VERSION 5.7 ;
  NOWIREEXTENSIONATPIN ON ;
  DIVIDERCHAR "/" ;
  BUSBITCHARS "[]" ;
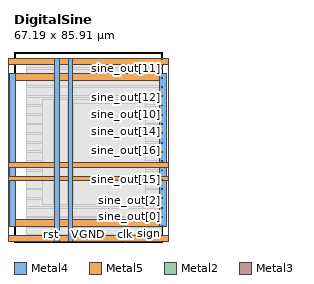
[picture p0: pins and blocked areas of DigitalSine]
MACRO DigitalSine
  CLASS BLOCK ;
  FOREIGN DigitalSine ;
  ORIGIN 0.000 0.000 ;
  SIZE 67.190 BY 85.910 ;
  PIN VGND
    DIRECTION INOUT ;
    USE GROUND ;
    PORT
      LAYER Metal4 ;
        RECT -9.240 0.120 -6.240 83.040 ;
    END
    PORT
      LAYER Metal4 ;
        RECT 72.960 0.120 75.960 83.040 ;
    END
    PORT
      LAYER Metal5 ;
        RECT -9.240 0.120 75.960 3.120 ;
    END
    PORT
      LAYER Metal5 ;
        RECT -9.240 80.040 75.960 83.040 ;
    END
    PORT
      LAYER Metal4 ;
        RECT 24.460 0.120 26.660 83.040 ;
    END
    PORT
      LAYER Metal5 ;
        RECT -9.240 33.820 75.960 36.020 ;
    END
  END VGND
  PIN VPWR
    DIRECTION INOUT ;
    USE POWER ;
    PORT
      LAYER Metal4 ;
        RECT -2.240 7.120 0.760 76.040 ;
    END
    PORT
      LAYER Metal4 ;
        RECT 65.960 7.120 68.960 76.040 ;
    END
    PORT
      LAYER Metal5 ;
        RECT -2.240 7.120 68.960 10.120 ;
    END
    PORT
      LAYER Metal5 ;
        RECT -2.240 73.040 68.960 76.040 ;
    END
    PORT
      LAYER Metal4 ;
        RECT 18.260 0.120 20.460 83.040 ;
    END
    PORT
      LAYER Metal5 ;
        RECT -9.240 27.620 75.960 29.820 ;
    END
  END VPWR
  PIN clk
    DIRECTION INPUT ;
    USE SIGNAL ;
    ANTENNAGATEAREA 1.450800 ;
    PORT
      LAYER Metal2 ;
        RECT 50.200 0.000 50.600 0.400 ;
    END
  END clk
  PIN rst
    DIRECTION INPUT ;
    USE SIGNAL ;
    ANTENNAGATEAREA 0.180700 ;
    PORT
      LAYER Metal2 ;
        RECT 16.600 0.000 17.000 0.400 ;
    END
  END rst
  PIN sign
    DIRECTION OUTPUT ;
    USE SIGNAL ;
    ANTENNADIFFAREA 0.708600 ;
    PORT
      LAYER Metal3 ;
        RECT 66.790 6.940 67.190 7.340 ;
    END
  END sign
  PIN signB
    DIRECTION OUTPUT ;
    USE SIGNAL ;
    ANTENNADIFFAREA 0.708600 ;
    PORT
      LAYER Metal3 ;
        RECT 66.790 2.740 67.190 3.140 ;
    END
  END signB
  PIN sine_out[0]
    DIRECTION OUTPUT ;
    USE SIGNAL ;
    ANTENNADIFFAREA 0.708600 ;
    PORT
      LAYER Metal3 ;
        RECT 66.790 11.140 67.190 11.540 ;
    END
  END sine_out[0]
  PIN sine_out[10]
    DIRECTION OUTPUT ;
    USE SIGNAL ;
    ANTENNADIFFAREA 0.708600 ;
    PORT
      LAYER Metal3 ;
        RECT 66.790 57.340 67.190 57.740 ;
    END
  END sine_out[10]
  PIN sine_out[11]
    DIRECTION OUTPUT ;
    USE SIGNAL ;
    ANTENNADIFFAREA 0.708600 ;
    PORT
      LAYER Metal3 ;
        RECT 66.790 78.340 67.190 78.740 ;
    END
  END sine_out[11]
  PIN sine_out[12]
    DIRECTION OUTPUT ;
    USE SIGNAL ;
    ANTENNADIFFAREA 0.708600 ;
    PORT
      LAYER Metal3 ;
        RECT 66.790 61.540 67.190 61.940 ;
    END
  END sine_out[12]
  PIN sine_out[13]
    DIRECTION OUTPUT ;
    USE SIGNAL ;
    ANTENNADIFFAREA 0.708600 ;
    PORT
      LAYER Metal3 ;
        RECT 66.790 69.940 67.190 70.340 ;
    END
  END sine_out[13]
  PIN sine_out[14]
    DIRECTION OUTPUT ;
    USE SIGNAL ;
    ANTENNADIFFAREA 0.708600 ;
    PORT
      LAYER Metal3 ;
        RECT 66.790 53.140 67.190 53.540 ;
    END
  END sine_out[14]
  PIN sine_out[15]
    DIRECTION OUTPUT ;
    USE SIGNAL ;
    ANTENNADIFFAREA 0.708600 ;
    PORT
      LAYER Metal3 ;
        RECT 66.790 27.940 67.190 28.340 ;
    END
  END sine_out[15]
  PIN sine_out[16]
    DIRECTION OUTPUT ;
    USE SIGNAL ;
    ANTENNADIFFAREA 0.708600 ;
    PORT
      LAYER Metal3 ;
        RECT 66.790 44.740 67.190 45.140 ;
    END
  END sine_out[16]
  PIN sine_out[17]
    DIRECTION OUTPUT ;
    USE SIGNAL ;
    ANTENNADIFFAREA 0.708600 ;
    PORT
      LAYER Metal3 ;
        RECT 66.790 40.540 67.190 40.940 ;
    END
  END sine_out[17]
  PIN sine_out[1]
    DIRECTION OUTPUT ;
    USE SIGNAL ;
    ANTENNADIFFAREA 0.708600 ;
    PORT
      LAYER Metal3 ;
        RECT 66.790 19.540 67.190 19.940 ;
    END
  END sine_out[1]
  PIN sine_out[2]
    DIRECTION OUTPUT ;
    USE SIGNAL ;
    ANTENNADIFFAREA 0.708600 ;
    PORT
      LAYER Metal3 ;
        RECT 66.790 15.340 67.190 15.740 ;
    END
  END sine_out[2]
  PIN sine_out[3]
    DIRECTION OUTPUT ;
    USE SIGNAL ;
    ANTENNADIFFAREA 0.708600 ;
    PORT
      LAYER Metal3 ;
        RECT 66.790 36.340 67.190 36.740 ;
    END
  END sine_out[3]
  PIN sine_out[4]
    DIRECTION OUTPUT ;
    USE SIGNAL ;
    ANTENNADIFFAREA 0.708600 ;
    PORT
      LAYER Metal3 ;
        RECT 66.790 23.740 67.190 24.140 ;
    END
  END sine_out[4]
  PIN sine_out[5]
    DIRECTION OUTPUT ;
    USE SIGNAL ;
    ANTENNADIFFAREA 0.708600 ;
    PORT
      LAYER Metal3 ;
        RECT 66.790 48.940 67.190 49.340 ;
    END
  END sine_out[5]
  PIN sine_out[6]
    DIRECTION OUTPUT ;
    USE SIGNAL ;
    ANTENNADIFFAREA 0.708600 ;
    PORT
      LAYER Metal3 ;
        RECT 66.790 32.140 67.190 32.540 ;
    END
  END sine_out[6]
  PIN sine_out[7]
    DIRECTION OUTPUT ;
    USE SIGNAL ;
    ANTENNADIFFAREA 0.708600 ;
    PORT
      LAYER Metal3 ;
        RECT 66.790 74.140 67.190 74.540 ;
    END
  END sine_out[7]
  PIN sine_out[8]
    DIRECTION OUTPUT ;
    USE SIGNAL ;
    ANTENNADIFFAREA 0.708600 ;
    PORT
      LAYER Metal3 ;
        RECT 66.790 65.740 67.190 66.140 ;
    END
  END sine_out[8]
  PIN sine_out[9]
    DIRECTION OUTPUT ;
    USE SIGNAL ;
    ANTENNADIFFAREA 0.708600 ;
    PORT
      LAYER Metal3 ;
        RECT 66.790 82.540 67.190 82.940 ;
    END
  END sine_out[9]
  OBS
      LAYER GatPoly ;
        RECT 5.760 14.970 60.960 68.190 ;
      LAYER Metal1 ;
        RECT 5.760 14.900 60.960 68.260 ;
      LAYER Metal2 ;
        RECT 5.655 0.610 65.385 82.885 ;
        RECT 5.655 0.100 16.390 0.610 ;
        RECT 17.210 0.100 49.990 0.610 ;
        RECT 50.810 0.100 65.385 0.610 ;
      LAYER Metal3 ;
        RECT 5.615 82.330 66.580 82.840 ;
        RECT 5.615 78.950 66.790 82.330 ;
        RECT 5.615 78.130 66.580 78.950 ;
        RECT 5.615 74.750 66.790 78.130 ;
        RECT 5.615 73.930 66.580 74.750 ;
        RECT 5.615 70.550 66.790 73.930 ;
        RECT 5.615 69.730 66.580 70.550 ;
        RECT 5.615 66.350 66.790 69.730 ;
        RECT 5.615 65.530 66.580 66.350 ;
        RECT 5.615 62.150 66.790 65.530 ;
        RECT 5.615 61.330 66.580 62.150 ;
        RECT 5.615 57.950 66.790 61.330 ;
        RECT 5.615 57.130 66.580 57.950 ;
        RECT 5.615 53.750 66.790 57.130 ;
        RECT 5.615 52.930 66.580 53.750 ;
        RECT 5.615 49.550 66.790 52.930 ;
        RECT 5.615 48.730 66.580 49.550 ;
        RECT 5.615 45.350 66.790 48.730 ;
        RECT 5.615 44.530 66.580 45.350 ;
        RECT 5.615 41.150 66.790 44.530 ;
        RECT 5.615 40.330 66.580 41.150 ;
        RECT 5.615 36.950 66.790 40.330 ;
        RECT 5.615 36.130 66.580 36.950 ;
        RECT 5.615 32.750 66.790 36.130 ;
        RECT 5.615 31.930 66.580 32.750 ;
        RECT 5.615 28.550 66.790 31.930 ;
        RECT 5.615 27.730 66.580 28.550 ;
        RECT 5.615 24.350 66.790 27.730 ;
        RECT 5.615 23.530 66.580 24.350 ;
        RECT 5.615 20.150 66.790 23.530 ;
        RECT 5.615 19.330 66.580 20.150 ;
        RECT 5.615 15.950 66.790 19.330 ;
        RECT 5.615 15.130 66.580 15.950 ;
        RECT 5.615 11.750 66.790 15.130 ;
        RECT 5.615 10.930 66.580 11.750 ;
        RECT 5.615 7.550 66.790 10.930 ;
        RECT 5.615 6.730 66.580 7.550 ;
        RECT 5.615 3.350 66.790 6.730 ;
        RECT 5.615 2.840 66.580 3.350 ;
      LAYER Metal4 ;
        RECT 12.860 17.075 18.050 64.405 ;
        RECT 20.670 17.075 24.250 64.405 ;
        RECT 26.870 17.075 59.625 64.405 ;
      LAYER Metal5 ;
        RECT 27.215 62.480 59.665 62.680 ;
  END
END DigitalSine
END LIBRARY

